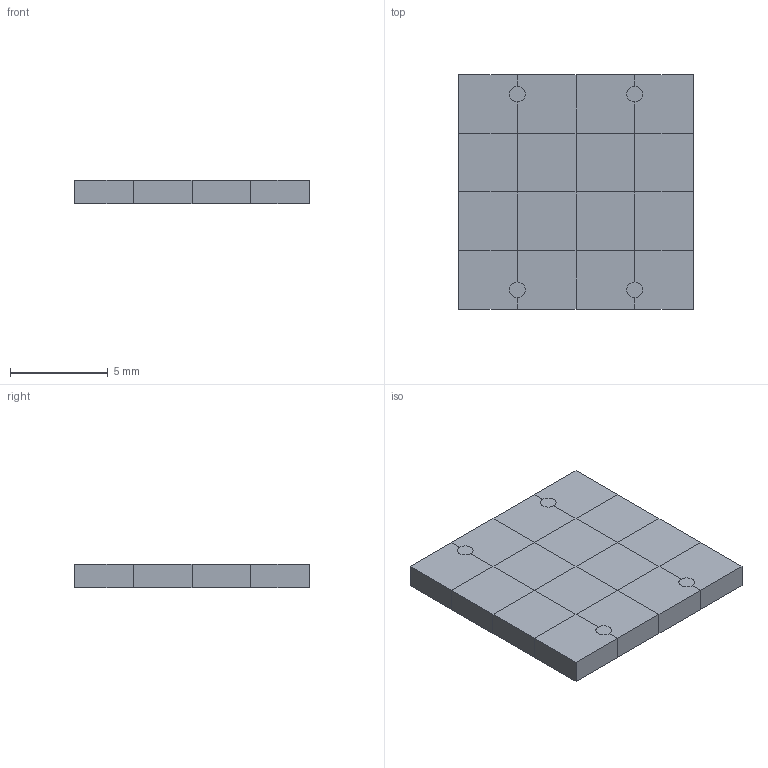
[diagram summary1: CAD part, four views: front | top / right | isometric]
STEP (ISO 10303-21) file: header records copied from the file, then geometry measured from it (millimetres).
FILE_DESCRIPTION(('Open CASCADE Model'),'2;1');
FILE_NAME('Open CASCADE Shape Model','2026-11-20T07:15:05',('Author'),( 'Open CASCADE'),'Open CASCADE STEP processor 7.9','Open CASCADE 7.9' ,'Unknown');
FILE_SCHEMA(('AUTOMOTIVE_DESIGN { 1 0 10303 214 1 1 1 1 }'));
Length unit declared in the file: millimetre
Products named in the file (3): manifold_A6; fluid; solid
Assembly tree (2 placements, depth 2):
  manifold_A6
    fluid
    solid
Bounding box: 12 x 12 x 1.2 mm (x, y, z)
Volume: 172.8 mm3; surface area: 1351.6 mm2
Topology: 2 solids, 2 shells, 1332 faces, 4524 edges, 2666 vertices
Faces by surface type: plane 1324, cylinder 8
Full cylindrical faces by diameter (mm): 0.8 x8
Entity records: 106702 total; most frequent: CARTESIAN_POINT 17621, DIRECTION 16258, LINE 13524, VECTOR 13524, ORIENTED_EDGE 9048, PCURVE 9048, DEFINITIONAL_REPRESENTATION 9048, EDGE_CURVE 4524
One B-rep face of a CAD part: STEP entity #56994.
In plain terms, the planar face has unit normal (0, 0, 1).
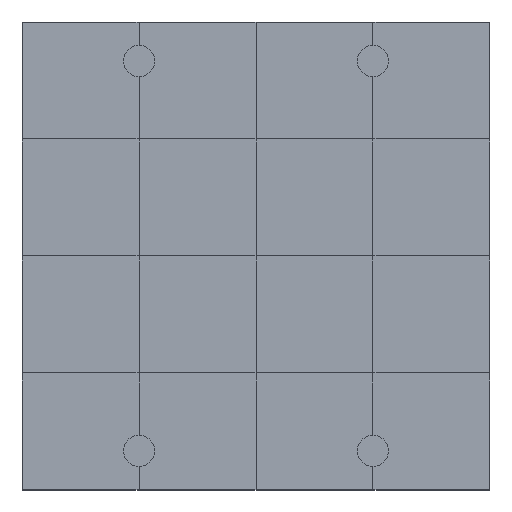
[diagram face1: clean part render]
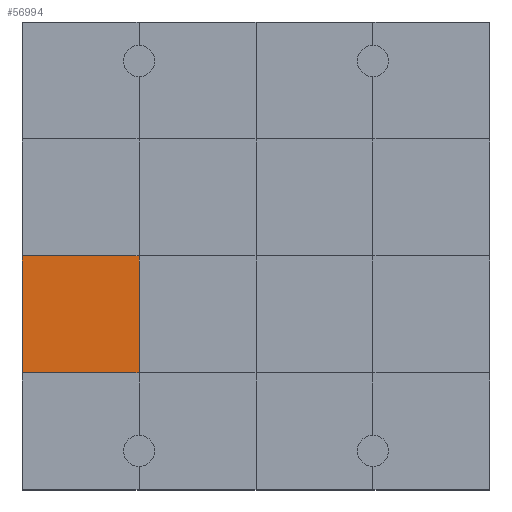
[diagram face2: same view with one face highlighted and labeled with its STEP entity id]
Its self-contained STEP definition (entity closure, numbers rounded to 3 decimals):
#56544 = VERTEX_POINT('',#56545);
#56545 = CARTESIAN_POINT('',(0.,3.,1.2));
#56559 = PLANE('',#56560);
#56560 = AXIS2_PLACEMENT_3D('',#56561,#56562,#56563);
#56561 = CARTESIAN_POINT('',(0.,3.,0.));
#56562 = DIRECTION('',(1.,0.,-0.));
#56563 = DIRECTION('',(0.,0.,1.));
#56585 = PLANE('',#56586);
#56586 = AXIS2_PLACEMENT_3D('',#56587,#56588,#56589);
#56587 = CARTESIAN_POINT('',(0.,0.,1.2));
#56588 = DIRECTION('',(0.,0.,1.));
#56589 = DIRECTION('',(1.,0.,-0.));
#56736 = VERTEX_POINT('',#56737);
#56737 = CARTESIAN_POINT('',(3.,3.,1.2));
#56758 = EDGE_CURVE('',#56544,#56736,#56759,.T.);
#56759 = SURFACE_CURVE('',#56760,(#56764,#56771),.PCURVE_S1.);
#56760 = LINE('',#56761,#56762);
#56761 = CARTESIAN_POINT('',(0.,3.,1.2));
#56762 = VECTOR('',#56763,1.);
#56763 = DIRECTION('',(1.,0.,-0.));
#56764 = PCURVE('',#56585,#56765);
#56765 = DEFINITIONAL_REPRESENTATION('',(#56766),#56770);
#56766 = LINE('',#56767,#56768);
#56767 = CARTESIAN_POINT('',(0.,3.));
#56768 = VECTOR('',#56769,1.);
#56769 = DIRECTION('',(1.,0.));
#56770 = ( GEOMETRIC_REPRESENTATION_CONTEXT(2) 
PARAMETRIC_REPRESENTATION_CONTEXT() REPRESENTATION_CONTEXT('2D SPACE',''
  ) );
#56771 = PCURVE('',#56772,#56777);
#56772 = PLANE('',#56773);
#56773 = AXIS2_PLACEMENT_3D('',#56774,#56775,#56776);
#56774 = CARTESIAN_POINT('',(0.,3.,1.2));
#56775 = DIRECTION('',(0.,0.,1.));
#56776 = DIRECTION('',(1.,0.,-0.));
#56777 = DEFINITIONAL_REPRESENTATION('',(#56778),#56782);
#56778 = LINE('',#56779,#56780);
#56779 = CARTESIAN_POINT('',(0.,0.));
#56780 = VECTOR('',#56781,1.);
#56781 = DIRECTION('',(1.,0.));
#56782 = ( GEOMETRIC_REPRESENTATION_CONTEXT(2) 
PARAMETRIC_REPRESENTATION_CONTEXT() REPRESENTATION_CONTEXT('2D SPACE',''
  ) );
#56817 = VERTEX_POINT('',#56818);
#56818 = CARTESIAN_POINT('',(0.,6.,1.2));
#56844 = EDGE_CURVE('',#56544,#56817,#56845,.T.);
#56845 = SURFACE_CURVE('',#56846,(#56850,#56857),.PCURVE_S1.);
#56846 = LINE('',#56847,#56848);
#56847 = CARTESIAN_POINT('',(0.,3.,1.2));
#56848 = VECTOR('',#56849,1.);
#56849 = DIRECTION('',(-0.,1.,0.));
#56850 = PCURVE('',#56559,#56851);
#56851 = DEFINITIONAL_REPRESENTATION('',(#56852),#56856);
#56852 = LINE('',#56853,#56854);
#56853 = CARTESIAN_POINT('',(1.2,0.));
#56854 = VECTOR('',#56855,1.);
#56855 = DIRECTION('',(0.,-1.));
#56856 = ( GEOMETRIC_REPRESENTATION_CONTEXT(2) 
PARAMETRIC_REPRESENTATION_CONTEXT() REPRESENTATION_CONTEXT('2D SPACE',''
  ) );
#56857 = PCURVE('',#56772,#56858);
#56858 = DEFINITIONAL_REPRESENTATION('',(#56859),#56863);
#56859 = LINE('',#56860,#56861);
#56860 = CARTESIAN_POINT('',(0.,0.));
#56861 = VECTOR('',#56862,1.);
#56862 = DIRECTION('',(0.,1.));
#56863 = ( GEOMETRIC_REPRESENTATION_CONTEXT(2) 
PARAMETRIC_REPRESENTATION_CONTEXT() REPRESENTATION_CONTEXT('2D SPACE',''
  ) );
#56994 = ADVANCED_FACE('',(#56995),#56772,.T.);
#56995 = FACE_BOUND('',#56996,.T.);
#56996 = EDGE_LOOP('',(#56997,#56998,#56999,#57027));
#56997 = ORIENTED_EDGE('',*,*,#56844,.F.);
#56998 = ORIENTED_EDGE('',*,*,#56758,.T.);
#56999 = ORIENTED_EDGE('',*,*,#57000,.T.);
#57000 = EDGE_CURVE('',#56736,#57001,#57003,.T.);
#57001 = VERTEX_POINT('',#57002);
#57002 = CARTESIAN_POINT('',(3.,6.,1.2));
#57003 = SURFACE_CURVE('',#57004,(#57008,#57015),.PCURVE_S1.);
#57004 = LINE('',#57005,#57006);
#57005 = CARTESIAN_POINT('',(3.,3.,1.2));
#57006 = VECTOR('',#57007,1.);
#57007 = DIRECTION('',(-0.,1.,0.));
#57008 = PCURVE('',#56772,#57009);
#57009 = DEFINITIONAL_REPRESENTATION('',(#57010),#57014);
#57010 = LINE('',#57011,#57012);
#57011 = CARTESIAN_POINT('',(3.,0.));
#57012 = VECTOR('',#57013,1.);
#57013 = DIRECTION('',(0.,1.));
#57014 = ( GEOMETRIC_REPRESENTATION_CONTEXT(2) 
PARAMETRIC_REPRESENTATION_CONTEXT() REPRESENTATION_CONTEXT('2D SPACE',''
  ) );
#57015 = PCURVE('',#57016,#57021);
#57016 = PLANE('',#57017);
#57017 = AXIS2_PLACEMENT_3D('',#57018,#57019,#57020);
#57018 = CARTESIAN_POINT('',(3.,3.,1.2));
#57019 = DIRECTION('',(0.,0.,1.));
#57020 = DIRECTION('',(1.,0.,-0.));
#57021 = DEFINITIONAL_REPRESENTATION('',(#57022),#57026);
#57022 = LINE('',#57023,#57024);
#57023 = CARTESIAN_POINT('',(0.,0.));
#57024 = VECTOR('',#57025,1.);
#57025 = DIRECTION('',(0.,1.));
#57026 = ( GEOMETRIC_REPRESENTATION_CONTEXT(2) 
PARAMETRIC_REPRESENTATION_CONTEXT() REPRESENTATION_CONTEXT('2D SPACE',''
  ) );
#57027 = ORIENTED_EDGE('',*,*,#57028,.F.);
#57028 = EDGE_CURVE('',#56817,#57001,#57029,.T.);
#57029 = SURFACE_CURVE('',#57030,(#57034,#57041),.PCURVE_S1.);
#57030 = LINE('',#57031,#57032);
#57031 = CARTESIAN_POINT('',(0.,6.,1.2));
#57032 = VECTOR('',#57033,1.);
#57033 = DIRECTION('',(1.,0.,-0.));
#57034 = PCURVE('',#56772,#57035);
#57035 = DEFINITIONAL_REPRESENTATION('',(#57036),#57040);
#57036 = LINE('',#57037,#57038);
#57037 = CARTESIAN_POINT('',(0.,3.));
#57038 = VECTOR('',#57039,1.);
#57039 = DIRECTION('',(1.,0.));
#57040 = ( GEOMETRIC_REPRESENTATION_CONTEXT(2) 
PARAMETRIC_REPRESENTATION_CONTEXT() REPRESENTATION_CONTEXT('2D SPACE',''
  ) );
#57041 = PCURVE('',#57042,#57047);
#57042 = PLANE('',#57043);
#57043 = AXIS2_PLACEMENT_3D('',#57044,#57045,#57046);
#57044 = CARTESIAN_POINT('',(0.,6.,1.2));
#57045 = DIRECTION('',(0.,0.,1.));
#57046 = DIRECTION('',(1.,0.,-0.));
#57047 = DEFINITIONAL_REPRESENTATION('',(#57048),#57052);
#57048 = LINE('',#57049,#57050);
#57049 = CARTESIAN_POINT('',(0.,0.));
#57050 = VECTOR('',#57051,1.);
#57051 = DIRECTION('',(1.,0.));
#57052 = ( GEOMETRIC_REPRESENTATION_CONTEXT(2) 
PARAMETRIC_REPRESENTATION_CONTEXT() REPRESENTATION_CONTEXT('2D SPACE',''
  ) );
